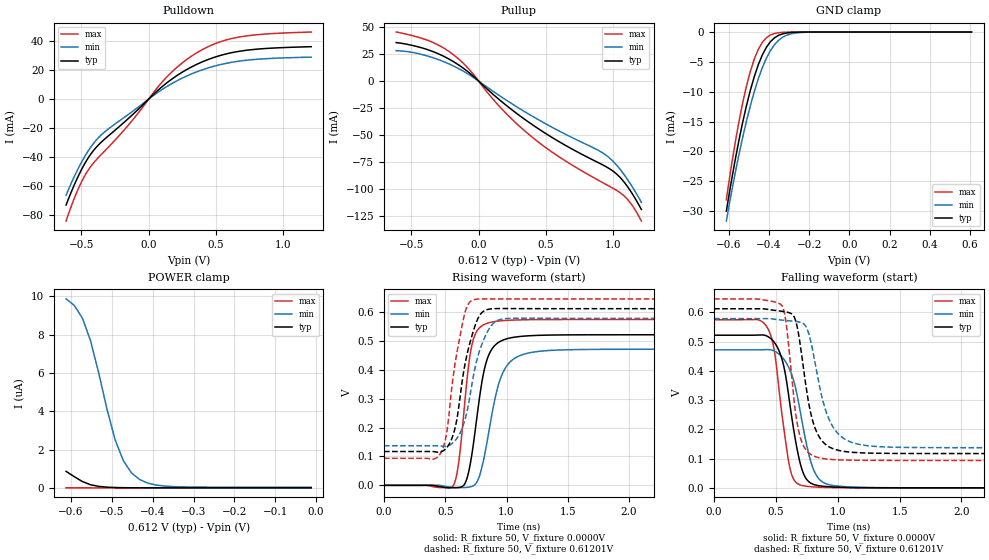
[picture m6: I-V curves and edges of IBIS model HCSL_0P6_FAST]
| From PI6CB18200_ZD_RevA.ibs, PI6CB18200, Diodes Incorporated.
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|   Model HCSL_OUT
[Model]   HCSL_0P6_FAST
Model_type Output
Vref=0.6000V
Vmeas=900mV
| variable   typ   min   max
C_comp   2.200pF   2.170pF   2.230pF
[Voltage Range]   0.61201V   0.57834V   0.64563V
[POWER Clamp Reference]   0.61201V   0.57834V   0.64563V
[GND Clamp Reference]   0.0000V   0.0000V   0.0000V
[Pullup Reference]   0.61201V   0.57834V   0.64563V
[Pulldown Reference]   0.0000V   0.0000V   0.0000V
[Temperature Range]   25   85   -40
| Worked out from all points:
|   slope of the pulldown table from 0 to 0.092 V, typ, clamps not added: 11.6 ohm
|   slope of the pullup table from 0 to 0.092 V, typ, clamps not added: 8.68 ohm
|   GND clamp passes 1 mA (typ) near -0.37 V on its own axis
|   falling waveform, R_fixture 50, V_fixture 0.0000V: 20-80 % time 122ps typ, 144ps min, 103ps max; typ from 0.522 V to 0 V
|   rising waveform, R_fixture 50, V_fixture 0.0000V: 20-80 % time 112ps typ, 141ps min, 85.6ps max; typ from 0 V to 0.522 V
|   falling waveform, R_fixture 50, V_fixture 0.61201V: 20-80 % time 119ps typ, 152ps min, 88.4ps max; typ from 0.612 V to 0.117 V
|   rising waveform, R_fixture 50, V_fixture 0.61201V: 20-80 % time 125ps typ, 140ps min, 109ps max; typ from 0.117 V to 0.612 V
[GND Clamp]
| Voltage   I(typ)   I(min)   I(max)
-612mV    -29.99mA   -31.66mA   -28.08mA
-572mV    -22.16mA   -24.32mA   -19.34mA
-552mV    -18.61mA   -20.97mA   -15.51mA
-512mV    -12.36mA   -14.94mA   -9.079mA
-492mV    -9.695mA   -12.28mA   -6.523mA
-472mV    -7.369mA   -9.876mA   -4.438mA
-432mV    -3.778mA   -5.894mA   -1.684mA
-392mV    -1.594mA   -3.08mA    -484.1uA
-352mV    -549.9uA   -1.379mA   -111.4uA
-312mV    -162.8uA   -534.4uA   -21.35uA
-232mV    -10.62uA   -61.45uA   -510.1nA
608mV     1.088nA    32.69nA    5.916pA
[POWER Clamp]
| Voltage   I(typ)   I(min)   I(max)
-612mV    861.3nA    9.861uA    1.622nA
-592mV    584.5nA    9.521uA    621.3pA
-572mV    326.4nA    8.851uA    247.2pA
-552mV    161.4nA    7.67uA     107.3pA
-512mV    36.25nA    4.113uA    34.36pA
-492mV    17.5nA     2.509uA    26.17pA
-472mV    8.826nA    1.421uA    22.46pA
-452mV    4.814nA    782.8nA    20.43pA
-432mV    2.956nA    433.1nA    19.01pA
-392mV    1.685nA    147.7nA    16.71pA
-352mV    1.395nA    67.95nA    14.59pA
-12.01mV  1.099nA    32.4nA     3.302pA
[Pulldown]
| Voltage   I(typ)   I(min)   I(max)
-612mV    -73mA      -66.14mA   -84.03mA
-552mV    -59.28mA   -53.51mA   -68.59mA
-492mV    -47.56mA   -42.53mA   -56.03mA
-432mV    -38.31mA   -33.48mA   -46.79mA
-352mV    -29.74mA   -24.73mA   -38.28mA
-152mV    -13.51mA   -10.63mA   -18.12mA
108mV     9.202mA    7.13mA     12.55mA
268mV     19.62mA    15.34mA    26.34mA
448mV     27.58mA    21.73mA    36.48mA
628mV     32.31mA    25.63mA    42.08mA
848mV     34.85mA    27.83mA    44.83mA
1.208V    36.24mA    29.04mA    46.35mA
[Pullup]
| Voltage   I(typ)   I(min)   I(max)
-612mV    35.7mA     28.22mA    45.49mA
-372mV    28.86mA    22.96mA    37.53mA
-212mV    19.86mA    15.46mA    26.73mA
-92.01mV  9.918mA    7.582mA    13.74mA
148mV     -16.65mA   -12.92mA   -22.6mA
348mV     -36mA      -28.82mA   -46.81mA
588mV     -55.49mA   -45.66mA   -69.46mA
908mV     -76.87mA   -65.61mA   -93.25mA
988mV     -82.6mA    -73.17mA   -98.72mA
1.088V    -94.91mA   -88.14mA   -107.4mA
1.148V    -105.9mA   -99.52mA   -116.7mA
1.208V    -119mA     -112.4mA   -129.7mA
[Falling Waveform]
R_fixture = 50
V_fixture = 0.0000V
V_fixture_min = 0.0000V
V_fixture_max = 0.0000V
|   Time   V(typ)   V(min)   V(max)
0s        521.6mV    471.5mV    574.5mV
350ps     522.1mV    471.5mV    575mV
440ps     515.7mV    472.4mV    540.2mV
490ps     495.4mV    466.8mV    461.3mV
540ps     451.9mV    451.2mV    280.2mV
610ps     294.6mV    405.5mV    73.25mV
710ps     63.43mV    229.7mV    8.233mV
820ps     9.766mV    48.12mV    2.841mV
980ps     2.602mV    6.949mV    765.6uV
5ns       10.03uV    12.5uV     7.762uV
[Rising Waveform]
R_fixture = 50
V_fixture = 0.0000V
V_fixture_min = 0.0000V
V_fixture_max = 0.0000V
|   Time   V(typ)   V(min)   V(max)
0s        4.666uV    5.74uV     3.844uV
570ps     -8.259mV   -7.435mV   2.236mV
610ps     -7.55mV    -7.857mV   80.2mV
660ps     5.497mV    -7.612mV   289.8mV
720ps     114.7mV    -3.356mV   490.9mV
800ps     360.2mV    63.96mV    553mV
860ps     456.2mV    196.1mV    563.7mV
980ps     504.6mV    398.6mV    570.8mV
1.22ns    518.9mV    461.6mV    573.9mV
5ns       521.6mV    471.5mV    574.5mV
[Falling Waveform]
R_fixture = 50
V_fixture = 0.61201V
V_fixture_min = 0.57834V
V_fixture_max = 0.64563V
|   Time   V(typ)   V(min)   V(max)
0s        612mV      578.3mV    645.6mV
550ps     603.2mV    573.3mV    622.3mV
590ps     600.5mV    571.5mV    537.5mV
640ps     589.8mV    569.5mV    323.2mV
690ps     507.5mV    566.6mV    183.3mV
760ps     301.4mV    534mV      121.5mV
840ps     181.5mV    373.9mV    103.8mV
970ps     132.5mV    202.4mV    96.43mV
1.22ns    119.1mV    145.1mV    93.96mV
5ns       117.2mV    137.2mV    93.58mV
[Rising Waveform]
R_fixture = 50
V_fixture = 0.61201V
V_fixture_min = 0.57834V
V_fixture_max = 0.64563V
|   Time   V(typ)   V(min)   V(max)
0s        117.2mV    137.2mV    93.58mV
460ps     115.5mV    136.7mV    109.6mV
510ps     129.4mV    135.7mV    176.6mV
560ps     169mV      146.2mV    361.3mV
630ps     335.5mV    189.5mV    537.7mV
680ps     457.3mV    260mV      621.7mV
740ps     548.8mV    401mV      643.9mV
860ps     610.4mV    543.6mV    645.9mV
990ps     612.4mV    577.5mV    645.7mV
5ns       612mV      578.3mV    645.6mV
[Ramp]
| variable   typ   min   max
dV/dt_r   0.31297V/112.21p   0.28288V/141.14p   0.34469V/85.594p
dV/dt_f   0.29690V/118.83p   0.26470V/151.73p   0.33122V/88.476p
R_load = 50
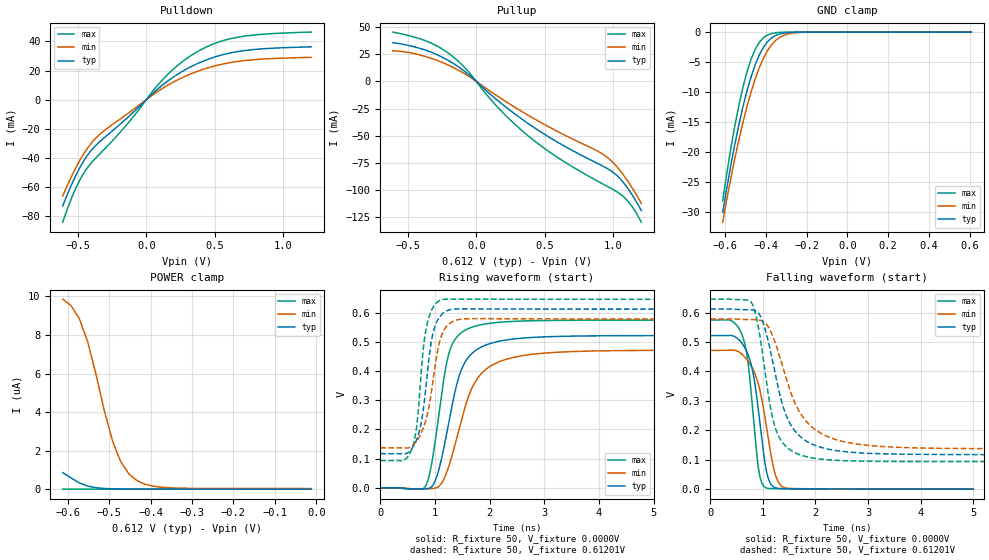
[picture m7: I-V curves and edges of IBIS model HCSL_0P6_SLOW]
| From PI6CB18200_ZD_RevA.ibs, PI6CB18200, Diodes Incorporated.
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[Model]   HCSL_0P6_SLOW
Model_type Output
Vref=0.6000V
Vmeas=900mV
| variable   typ   min   max
C_comp   2.200pF   2.170pF   2.230pF
[Voltage Range]   0.61201V   0.57834V   0.64563V
[POWER Clamp Reference]   0.61201V   0.57834V   0.64563V
[GND Clamp Reference]   0.0000V   0.0000V   0.0000V
[Pullup Reference]   0.61201V   0.57834V   0.64563V
[Pulldown Reference]   0.0000V   0.0000V   0.0000V
[Temperature Range]   25   85   -40
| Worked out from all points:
|   slope of the pulldown table from 0 to 0.092 V, typ, clamps not added: 11.6 ohm
|   slope of the pullup table from 0 to 0.092 V, typ, clamps not added: 8.68 ohm
|   GND clamp passes 1 mA (typ) near -0.37 V on its own axis
|   falling waveform, R_fixture 50, V_fixture 0.0000V: 20-80 % time 242ps typ, 298ps min, 191ps max; typ from 0.522 V to 0 V
|   rising waveform, R_fixture 50, V_fixture 0.0000V: 20-80 % time 387ps typ, 499ps min, 286ps max; typ from 0 V to 0.522 V
|   falling waveform, R_fixture 50, V_fixture 0.61201V: 20-80 % time 449ps typ, 602ps min, 315ps max; typ from 0.612 V to 0.117 V
|   rising waveform, R_fixture 50, V_fixture 0.61201V: 20-80 % time 203ps typ, 248ps min, 168ps max; typ from 0.117 V to 0.612 V
[GND Clamp]
| Voltage   I(typ)   I(min)   I(max)
-612mV    -29.99mA   -31.66mA   -28.08mA
-572mV    -22.16mA   -24.32mA   -19.34mA
-552mV    -18.61mA   -20.97mA   -15.51mA
-512mV    -12.36mA   -14.94mA   -9.079mA
-492mV    -9.695mA   -12.28mA   -6.523mA
-472mV    -7.369mA   -9.876mA   -4.438mA
-432mV    -3.778mA   -5.894mA   -1.684mA
-392mV    -1.594mA   -3.08mA    -484.1uA
-352mV    -549.9uA   -1.379mA   -111.4uA
-312mV    -162.8uA   -534.4uA   -21.35uA
-232mV    -10.62uA   -61.45uA   -510.1nA
608mV     1.088nA    32.69nA    5.916pA
[POWER Clamp]
| Voltage   I(typ)   I(min)   I(max)
-612mV    861.3nA    9.861uA    1.622nA
-592mV    584.5nA    9.521uA    621.3pA
-572mV    326.4nA    8.851uA    247.2pA
-552mV    161.4nA    7.67uA     107.3pA
-512mV    36.25nA    4.113uA    34.36pA
-492mV    17.5nA     2.509uA    26.17pA
-472mV    8.826nA    1.421uA    22.46pA
-452mV    4.814nA    782.8nA    20.43pA
-432mV    2.956nA    433.1nA    19.01pA
-392mV    1.685nA    147.7nA    16.71pA
-352mV    1.395nA    67.95nA    14.59pA
-12.01mV  1.099nA    32.4nA     3.302pA
[Pulldown]
| Voltage   I(typ)   I(min)   I(max)
-612mV    -73mA      -66.14mA   -84.03mA
-552mV    -59.28mA   -53.51mA   -68.59mA
-492mV    -47.56mA   -42.53mA   -56.03mA
-432mV    -38.31mA   -33.48mA   -46.79mA
-352mV    -29.74mA   -24.73mA   -38.28mA
-152mV    -13.51mA   -10.63mA   -18.12mA
108mV     9.202mA    7.13mA     12.55mA
268mV     19.62mA    15.34mA    26.34mA
448mV     27.58mA    21.73mA    36.48mA
628mV     32.31mA    25.63mA    42.08mA
848mV     34.85mA    27.83mA    44.83mA
1.208V    36.24mA    29.04mA    46.35mA
[Pullup]
| Voltage   I(typ)   I(min)   I(max)
-612mV    35.7mA     28.22mA    45.49mA
-372mV    28.86mA    22.96mA    37.53mA
-212mV    19.86mA    15.46mA    26.73mA
-92.01mV  9.918mA    7.582mA    13.74mA
148mV     -16.65mA   -12.92mA   -22.6mA
348mV     -36mA      -28.82mA   -46.81mA
588mV     -55.49mA   -45.66mA   -69.46mA
908mV     -76.87mA   -65.61mA   -93.25mA
988mV     -82.6mA    -73.17mA   -98.72mA
1.088V    -94.91mA   -88.14mA   -107.4mA
1.148V    -105.9mA   -99.52mA   -116.7mA
1.208V    -119mA     -112.4mA   -129.7mA
[Falling Waveform]
R_fixture = 50
V_fixture = 0.0000V
V_fixture_min = 0.0000V
V_fixture_max = 0.0000V
|   Time   V(typ)   V(min)   V(max)
0s        521.6mV    471.5mV    574.5mV
400ps     522mV      471.9mV    572.1mV
620ps     491.4mV    455.6mV    516.7mV
720ps     456.3mV    435.4mV    427.2mV
820ps     388.6mV    404.1mV    240.3mV
930ps     245.5mV    346.3mV    55.54mV
1.04ns    89.64mV    244.4mV    6.396mV
1.23ns    5.038mV    53.9mV     1.793mV
1.41ns    1.808mV    5.117mV    1.401mV
5ns       18.06uV    35.2uV     9.849uV
[Rising Waveform]
R_fixture = 50
V_fixture = 0.0000V
V_fixture_min = 0.0000V
V_fixture_max = 0.0000V
|   Time   V(typ)   V(min)   V(max)
0s        4.784uV    5.905uV    3.914uV
820ps     -3.36mV    -2.914mV   4.181mV
920ps     732.2uV    -2.643mV   63.21mV
1.02ns    32.1mV     208.6uV    180.1mV
1.26ns    231.1mV    77.9mV     463.3mV
1.46ns    393.4mV    214.8mV    528.1mV
1.72ns    467.4mV    357.9mV    552.9mV
2.14ns    500.8mV    429.2mV    566.4mV
3ns       517.2mV    461.5mV    573.1mV
10ns      521.6mV    471.5mV    574.5mV
[Falling Waveform]
R_fixture = 50
V_fixture = 0.61201V
V_fixture_min = 0.57834V
V_fixture_max = 0.64563V
|   Time   V(typ)   V(min)   V(max)
0s        612mV      578.3mV    645.6mV
800ps     608.6mV    576.1mV    628.4mV
1ns       567.4mV    570.3mV    453mV
1.14ns    473.2mV    539.2mV    282mV
1.24ns    388.1mV    494.4mV    206.1mV
1.44ns    251.9mV    378.2mV    145.1mV
1.72ns    177.1mV    255.5mV    115.7mV
2.22ns    136.7mV    179.4mV    100.2mV
3.2ns     120.5mV    145.6mV    94.42mV
10ns      117.2mV    137.2mV    93.58mV
[Rising Waveform]
R_fixture = 50
V_fixture = 0.61201V
V_fixture_min = 0.57834V
V_fixture_max = 0.64563V
|   Time   V(typ)   V(min)   V(max)
0s        117.2mV    137.2mV    93.58mV
420ps     116.5mV    137.1mV    93.3mV
580ps     135.3mV    143.6mV    134.3mV
670ps     168mV      162mV      217.2mV
780ps     257.5mV    202mV      465.2mV
840ps     354.9mV    236.8mV    546.6mV
950ps     517.4mV    348.9mV    613.1mV
1.1ns     589mV      510.9mV    642.7mV
1.55ns    613mV      578.9mV    646.2mV
7ns       612mV      578.3mV    645.6mV
[Ramp]
| variable   typ   min   max
dV/dt_r   0.31297V/388.46p   0.28288V/498.66p   0.34469V/285.96p
dV/dt_f   0.29690V/449.40p   0.26470V/602.51p   0.33122V/315.07p
R_load = 50
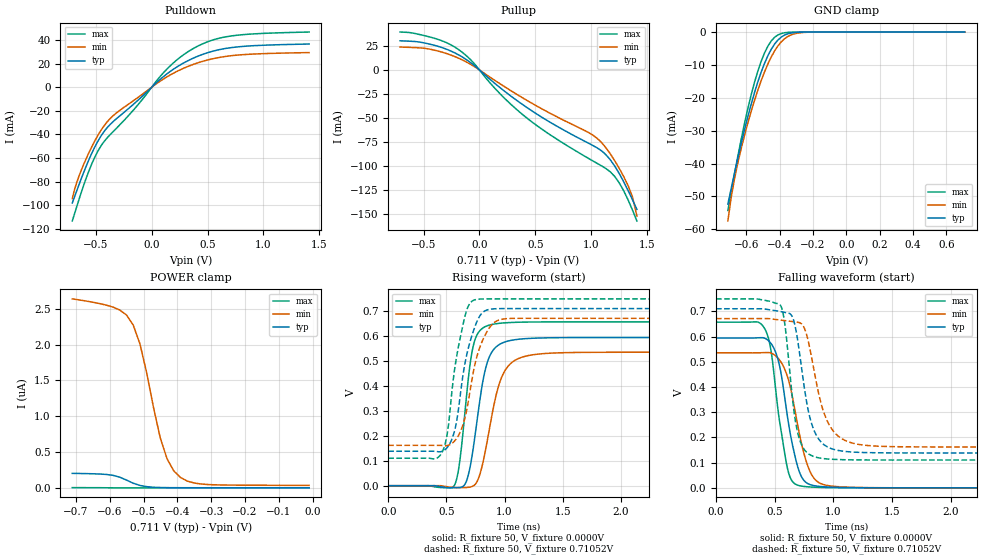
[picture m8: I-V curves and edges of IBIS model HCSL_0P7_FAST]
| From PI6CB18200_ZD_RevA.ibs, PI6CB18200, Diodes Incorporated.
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[Model]   HCSL_0P7_FAST
Model_type Output
Vref=0.7000V
Vmeas=900mV
| variable   typ   min   max
C_comp   2.200pF   2.170pF   2.230pF
[Voltage Range]   0.71052V   0.67147V   0.74949V
[POWER Clamp Reference]   0.71052V   0.67147V   0.74949V
[GND Clamp Reference]   0.0000V   0.0000V   0.0000V
[Pullup Reference]   0.71052V   0.67147V   0.74949V
[Pulldown Reference]   0.0000V   0.0000V   0.0000V
[Temperature Range]   25   85   -40
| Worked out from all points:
|   slope of the pulldown table from 0 to 0.107 V, typ, clamps not added: 11.7 ohm
|   slope of the pullup table from 0 to 0.107 V, typ, clamps not added: 9.74 ohm
|   GND clamp passes 1 mA (typ) near -0.37 V on its own axis
|   falling waveform, R_fixture 50, V_fixture 0.0000V: 20-80 % time 131ps typ, 151ps min, 113ps max; typ from 0.594 V to 0 V
|   rising waveform, R_fixture 50, V_fixture 0.0000V: 20-80 % time 119ps typ, 149ps min, 92.5ps max; typ from 0 V to 0.594 V
|   falling waveform, R_fixture 50, V_fixture 0.71052V: 20-80 % time 124ps typ, 157ps min, 93.3ps max; typ from 0.711 V to 0.138 V
|   rising waveform, R_fixture 50, V_fixture 0.71052V: 20-80 % time 130ps typ, 144ps min, 115ps max; typ from 0.138 V to 0.711 V
[GND Clamp]
| Voltage   I(typ)   I(min)   I(max)
-710.5mV  -52.32mA   -57.46mA   -54.26mA
-690.5mV  -47.56mA   -50.29mA   -48.61mA
-650.5mV  -38.34mA   -39.76mA   -37.72mA
-590.5mV  -25.69mA   -27.63mA   -23.23mA
-550.5mV  -18.37mA   -20.75mA   -15.25mA
-490.5mV  -9.518mA   -12.1mA    -6.355mA
-470.5mV  -7.215mA   -9.716mA   -4.304mA
-430.5mV  -3.675mA   -5.774mA   -1.616mA
-390.5mV  -1.539mA   -3mA       -460.2uA
-350.5mV  -527.1uA   -1.335mA   -105.2uA
-270.5mV  -41.31uA   -180uA     -3.245uA
709.5mV   1.155nA    34.32nA    1.818pA
[POWER Clamp]
| Voltage   I(typ)   I(min)   I(max)
-710.5mV  202.2nA    2.638uA    2.798nA
-570.5mV  149.4nA    2.483uA    234pA
-550.5mV  108.8nA    2.414uA    105.5pA
-530.5mV  64.81nA    2.274uA    56.58pA
-510.5mV  33.41nA    2.009uA    37.7pA
-490.5mV  16.56nA    1.602uA    30pA
-450.5mV  4.682nA    697.5nA    24.52pA
-430.5mV  2.929nA    406.4nA    23.13pA
-410.5mV  2.112nA    236.4nA    21.95pA
-390.5mV  1.728nA    143.7nA    20.85pA
-310.5mV  1.373nA    46.52nA    16.62pA
-10.52mV  1.163nA    33.88nA    838.6fA
[Pulldown]
| Voltage   I(typ)   I(min)   I(max)
-710.5mV  -98.12mA   -94.39mA   -113.4mA
-650.5mV  -82.61mA   -75.33mA   -95.15mA
-530.5mV  -54.84mA   -49.39mA   -63.74mA
-470.5mV  -43.95mA   -39.05mA   -52.33mA
-390.5mV  -33.42mA   -28.49mA   -42.08mA
-150.5mV  -13.38mA   -10.53mA   -17.95mA
109.5mV   9.316mA    7.219mA    12.7mA
249.5mV   18.59mA    14.52mA    24.99mA
449.5mV   27.63mA    21.78mA    36.54mA
649.5mV   32.68mA    25.95mA    42.5mA
909.5mV   35.21mA    28.14mA    45.22mA
1.409V    36.65mA    29.38mA    46.82mA
[Pullup]
| Voltage   I(typ)   I(min)   I(max)
-710.5mV  30.31mA    23.83mA    39.46mA
-390.5mV  25.24mA    20.24mA    32.51mA
-190.5mV  15.92mA    12.39mA    21.49mA
-70.52mV  6.87mA     5.237mA    9.578mA
169.5mV   -17.03mA   -13.28mA   -23mA
389.5mV   -36.3mA    -29.26mA   -46.74mA
649.5mV   -55.62mA   -46.15mA   -68.79mA
1.029V    -79.58mA   -69.05mA   -95.65mA
1.169V    -93.26mA   -87.06mA   -105.9mA
1.289V    -116mA     -110.6mA   -125.4mA
1.369V    -135.1mA   -132mA     -145.7mA
1.409V    -145.1mA   -152.1mA   -157.3mA
[Falling Waveform]
R_fixture = 50
V_fixture = 0.0000V
V_fixture_min = 0.0000V
V_fixture_max = 0.0000V
|   Time   V(typ)   V(min)   V(max)
0s        594.4mV    535.5mV    657.3mV
350ps     595.1mV    535.6mV    658.2mV
420ps     592.6mV    536.7mV    627.2mV
470ps     571.8mV    534.4mV    540.8mV
530ps     506.3mV    513.6mV    302.8mV
610ps     279.3mV    439.6mV    74.7mV
700ps     77.69mV    239.1mV    9.97mV
810ps     11.58mV    56.54mV    3.221mV
980ps     2.696mV    7.269mV    816.9uV
5ns       11.41uV    14.18uV    8.872uV
[Rising Waveform]
R_fixture = 50
V_fixture = 0.0000V
V_fixture_min = 0.0000V
V_fixture_max = 0.0000V
|   Time   V(typ)   V(min)   V(max)
0s        5.307uV    6.449uV    4.595uV
570ps     -8.244mV   -7.434mV   2.191mV
610ps     -7.477mV   -7.853mV   81.04mV
670ps     15.19mV    -7.322mV   345mV
730ps     147.3mV    -1.181mV   558.5mV
810ps     409.2mV    84.22mV    631.3mV
870ps     517.2mV    227.6mV    644.3mV
1ns       576.1mV    458.8mV    653.2mV
1.24ns    591.5mV    524.9mV    656.6mV
5ns       594.4mV    535.5mV    657.3mV
[Falling Waveform]
R_fixture = 50
V_fixture = 0.71052V
V_fixture_min = 0.67147V
V_fixture_max = 0.74949V
|   Time   V(typ)   V(min)   V(max)
0s        710.5mV    671.5mV    749.5mV
550ps     699.5mV    665.8mV    723.6mV
590ps     695.5mV    663.5mV    637.2mV
650ps     679mV      659.8mV    360.7mV
690ps     602.8mV    657.3mV    231.2mV
760ps     374.2mV    625.2mV    147.3mV
850ps     213mV      429.1mV    121.7mV
990ps     154.5mV    231.2mV    113.3mV
1.24ns    140.3mV    170.6mV    110.7mV
5ns       138.2mV    161.9mV    110.3mV
[Rising Waveform]
R_fixture = 50
V_fixture = 0.71052V
V_fixture_min = 0.67147V
V_fixture_max = 0.74949V
|   Time   V(typ)   V(min)   V(max)
0s        138.2mV    161.9mV    110.3mV
460ps     137.3mV    161.4mV    131.6mV
510ps     154.7mV    161.1mV    215mV
560ps     203.2mV    174.4mV    429.1mV
630ps     401.4mV    227.7mV    617.7mV
690ps     554.2mV    341.9mV    722mV
750ps     643.5mV    495.8mV    746.2mV
870ps     707.3mV    633.4mV    749.4mV
1.02ns    710.5mV    670.1mV    749.4mV
5ns       710.5mV    671.5mV    749.5mV
[Ramp]
| variable   typ   min   max
dV/dt_r   0.35665V/119.45p   0.32129V/148.62p   0.39436V/92.531p
dV/dt_f   0.34337V/123.98p   0.30571V/157.20p   0.38352V/93.305p
R_load = 50
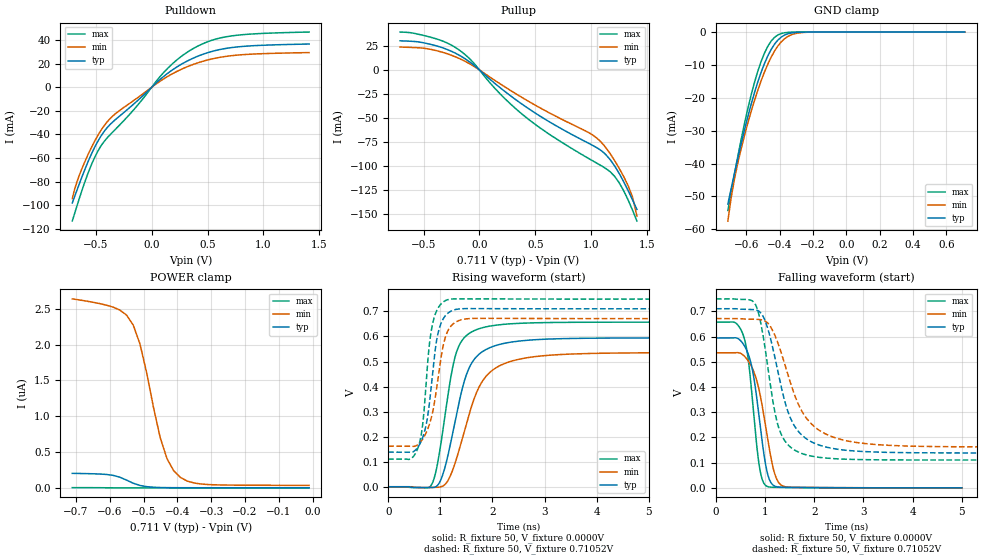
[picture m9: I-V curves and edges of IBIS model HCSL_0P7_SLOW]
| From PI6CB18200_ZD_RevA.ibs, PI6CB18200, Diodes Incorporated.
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[Model]   HCSL_0P7_SLOW
Model_type Output
Vref=0.7000V
Vmeas=900mV
| variable   typ   min   max
C_comp   2.200pF   2.170pF   2.230pF
[Voltage Range]   0.71052V   0.67147V   0.74949V
[POWER Clamp Reference]   0.71052V   0.67147V   0.74949V
[GND Clamp Reference]   0.0000V   0.0000V   0.0000V
[Pullup Reference]   0.71052V   0.67147V   0.74949V
[Pulldown Reference]   0.0000V   0.0000V   0.0000V
[Temperature Range]   25   85   -40
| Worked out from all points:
|   slope of the pulldown table from 0 to 0.107 V, typ, clamps not added: 11.7 ohm
|   slope of the pullup table from 0 to 0.107 V, typ, clamps not added: 9.74 ohm
|   GND clamp passes 1 mA (typ) near -0.37 V on its own axis
|   falling waveform, R_fixture 50, V_fixture 0.0000V: 20-80 % time 252ps typ, 306ps min, 205ps max; typ from 0.594 V to 0 V
|   rising waveform, R_fixture 50, V_fixture 0.0000V: 20-80 % time 416ps typ, 527ps min, 313ps max; typ from 0 V to 0.594 V
|   falling waveform, R_fixture 50, V_fixture 0.71052V: 20-80 % time 471ps typ, 624ps min, 335ps max; typ from 0.711 V to 0.138 V
|   rising waveform, R_fixture 50, V_fixture 0.71052V: 20-80 % time 206ps typ, 250ps min, 170ps max; typ from 0.138 V to 0.711 V
[GND Clamp]
| Voltage   I(typ)   I(min)   I(max)
-710.5mV  -52.32mA   -57.46mA   -54.26mA
-690.5mV  -47.56mA   -50.29mA   -48.61mA
-650.5mV  -38.34mA   -39.76mA   -37.72mA
-590.5mV  -25.69mA   -27.63mA   -23.23mA
-550.5mV  -18.37mA   -20.75mA   -15.25mA
-490.5mV  -9.518mA   -12.1mA    -6.355mA
-470.5mV  -7.215mA   -9.716mA   -4.304mA
-430.5mV  -3.675mA   -5.774mA   -1.616mA
-390.5mV  -1.539mA   -3mA       -460.2uA
-350.5mV  -527.1uA   -1.335mA   -105.2uA
-270.5mV  -41.31uA   -180uA     -3.245uA
709.5mV   1.155nA    34.32nA    1.818pA
[POWER Clamp]
| Voltage   I(typ)   I(min)   I(max)
-710.5mV  202.2nA    2.638uA    2.798nA
-570.5mV  149.4nA    2.483uA    234pA
-550.5mV  108.8nA    2.414uA    105.5pA
-530.5mV  64.81nA    2.274uA    56.58pA
-510.5mV  33.41nA    2.009uA    37.7pA
-490.5mV  16.56nA    1.602uA    30pA
-450.5mV  4.682nA    697.5nA    24.52pA
-430.5mV  2.929nA    406.4nA    23.13pA
-410.5mV  2.112nA    236.4nA    21.95pA
-390.5mV  1.728nA    143.7nA    20.85pA
-310.5mV  1.373nA    46.52nA    16.62pA
-10.52mV  1.163nA    33.88nA    838.6fA
[Pulldown]
| Voltage   I(typ)   I(min)   I(max)
-710.5mV  -98.12mA   -94.39mA   -113.4mA
-650.5mV  -82.61mA   -75.33mA   -95.15mA
-530.5mV  -54.84mA   -49.39mA   -63.74mA
-470.5mV  -43.95mA   -39.05mA   -52.33mA
-390.5mV  -33.42mA   -28.49mA   -42.08mA
-150.5mV  -13.38mA   -10.53mA   -17.95mA
109.5mV   9.316mA    7.219mA    12.7mA
249.5mV   18.59mA    14.52mA    24.99mA
449.5mV   27.63mA    21.78mA    36.54mA
649.5mV   32.68mA    25.95mA    42.5mA
909.5mV   35.21mA    28.14mA    45.22mA
1.409V    36.65mA    29.38mA    46.82mA
[Pullup]
| Voltage   I(typ)   I(min)   I(max)
-710.5mV  30.31mA    23.83mA    39.46mA
-390.5mV  25.24mA    20.24mA    32.51mA
-190.5mV  15.92mA    12.39mA    21.49mA
-70.52mV  6.87mA     5.237mA    9.578mA
169.5mV   -17.03mA   -13.28mA   -23mA
389.5mV   -36.3mA    -29.26mA   -46.74mA
649.5mV   -55.62mA   -46.15mA   -68.79mA
1.029V    -79.58mA   -69.05mA   -95.65mA
1.169V    -93.26mA   -87.06mA   -105.9mA
1.289V    -116mA     -110.6mA   -125.4mA
1.369V    -135.1mA   -132mA     -145.7mA
1.409V    -145.1mA   -152.1mA   -157.3mA
[Falling Waveform]
R_fixture = 50
V_fixture = 0.0000V
V_fixture_min = 0.0000V
V_fixture_max = 0.0000V
|   Time   V(typ)   V(min)   V(max)
0s        594.4mV    535.5mV    657.3mV
390ps     595.2mV    535.9mV    655.2mV
570ps     566mV      523.6mV    595.9mV
650ps     533.6mV    505mV      517.8mV
730ps     478.8mV    477.8mV    371.2mV
870ps     292.5mV    394.2mV    100.8mV
1.02ns    80.71mV    230.5mV    7.919mV
1.19ns    7.292mV    58.81mV    2.179mV
1.38ns    2.169mV    5.766mV    1.532mV
5ns       19.5uV     37.07uV    10.95uV
[Rising Waveform]
R_fixture = 50
V_fixture = 0.0000V
V_fixture_min = 0.0000V
V_fixture_max = 0.0000V
|   Time   V(typ)   V(min)   V(max)
0s        5.398uV    6.616uV    4.481uV
840ps     -3.235mV   -2.883mV   11.44mV
1.04ns    44.16mV    1.97mV     212.7mV
1.2ns     176.6mV    47.45mV    435.9mV
1.3ns     278mV      105.1mV    531mV
1.52ns    458.6mV    265.7mV    607.1mV
1.76ns    532.2mV    404.8mV    632.1mV
2.18ns    570.6mV    487.4mV    647.9mV
3.1ns     589.9mV    525.3mV    655.8mV
10ns      594.4mV    535.5mV    657.3mV
[Falling Waveform]
R_fixture = 50
V_fixture = 0.71052V
V_fixture_min = 0.67147V
V_fixture_max = 0.74949V
|   Time   V(typ)   V(min)   V(max)
0s        710.5mV    671.5mV    749.5mV
800ps     706mV      668.8mV    727.9mV
1.02ns    651.7mV    658.9mV    525.6mV
1.18ns    533.5mV    612.9mV    318mV
1.28ns    442.6mV    562.9mV    235.9mV
1.5ns     282.9mV    425.7mV    164.1mV
1.78ns    203.4mV    293.1mV    134mV
2.28ns    159.8mV    209.1mV    117.4mV
3.2ns     142.4mV    172.5mV    111.3mV
10ns      138.2mV    161.9mV    110.3mV
[Rising Waveform]
R_fixture = 50
V_fixture = 0.71052V
V_fixture_min = 0.67147V
V_fixture_max = 0.74949V
|   Time   V(typ)   V(min)   V(max)
0s        138.2mV    161.9mV    110.3mV
420ps     137.6mV    161.9mV    110.5mV
570ps     158.1mV    168.8mV    154.6mV
660ps     195.7mV    190.1mV    246.5mV
730ps     249.4mV    216.4mV    421mV
840ps     430.8mV    286.7mV    638.8mV
950ps     607.7mV    424.7mV    711.4mV
1.11ns    686.4mV    605.4mV    744.6mV
1.55ns    711.4mV    671.4mV    750.1mV
7ns       710.5mV    671.5mV    749.5mV
[Ramp]
| variable   typ   min   max
dV/dt_r   0.35665V/417.59p   0.32130V/527.39p   0.39436V/313.27p
dV/dt_f   0.34337V/471.33p   0.30571V/624.34p   0.38352V/334.74p
R_load = 50
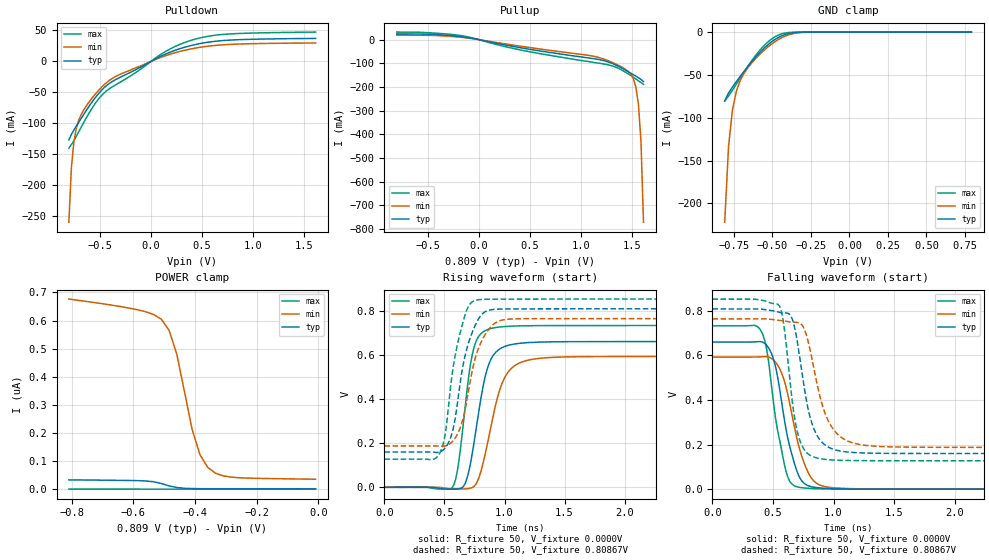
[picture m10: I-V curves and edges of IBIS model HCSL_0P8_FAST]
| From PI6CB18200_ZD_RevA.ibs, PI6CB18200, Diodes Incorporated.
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[Model]   HCSL_0P8_FAST
Model_type Output
Vref=0.8000V
Vmeas=900mV
| variable   typ   min   max
C_comp   2.200pF   2.170pF   2.230pF
[Voltage Range]   0.80867V   0.76428V   0.85294V
[POWER Clamp Reference]   0.80867V   0.76428V   0.85294V
[GND Clamp Reference]   0.0000V   0.0000V   0.0000V
[Pullup Reference]   0.80867V   0.76428V   0.85294V
[Pulldown Reference]   0.0000V   0.0000V   0.0000V
[Temperature Range]   25   85   -40
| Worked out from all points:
|   slope of the pulldown table from 0 to 0.121 V, typ, clamps not added: 11.9 ohm
|   slope of the pullup table from 0 to 0.121 V, typ, clamps not added: 11.2 ohm
|   GND clamp passes 1 mA (typ) near -0.37 V on its own axis
|   falling waveform, R_fixture 50, V_fixture 0.0000V: 20-80 % time 139ps typ, 157ps min, 121ps max; typ from 0.66 V to 0 V
|   rising waveform, R_fixture 50, V_fixture 0.0000V: 20-80 % time 127ps typ, 157ps min, 99.6ps max; typ from 0 V to 0.66 V
|   falling waveform, R_fixture 50, V_fixture 0.80867V: 20-80 % time 130ps typ, 164ps min, 98.3ps max; typ from 0.809 V to 0.16 V
|   rising waveform, R_fixture 50, V_fixture 0.80867V: 20-80 % time 134ps typ, 147ps min, 120ps max; typ from 0.16 V to 0.809 V
[GND Clamp]
| Voltage   I(typ)   I(min)   I(max)
-808.7mV  -80.37mA   -222mA     -80.74mA
-783.7mV  -71.17mA   -133.6mA   -74.56mA
-758.7mV  -64.24mA   -91.22mA   -67.91mA
-733.7mV  -57.98mA   -69.4mA    -60.91mA
-708.7mV  -51.92mA   -56.75mA   -53.79mA
-658.7mV  -40.22mA   -41.7mA    -39.91mA
-583.7mV  -24.39mA   -26.41mA   -21.78mA
-508.7mV  -11.91mA   -14.51mA   -8.63mA
-458.7mV  -6.021mA   -8.437mA   -3.317mA
-408.7mV  -2.346mA   -4.117mA   -840.2uA
-308.7mV  -146.6uA   -492.3uA   -18.47uA
791.3mV   1.208nA    35.61nA    1.245pA
[POWER Clamp]
| Voltage   I(typ)   I(min)   I(max)
-808.7mV  33.02nA    676.5nA    257.7pA
-583.7mV  30.32nA    637.8nA    188.8pA
-533.7mV  26.33nA    621.6nA    64.6pA
-508.7mV  20.08nA    604.6nA    40.81pA
-483.7mV  11.74nA    565.4nA    32.71pA
-458.7mV  5.847nA    479.8nA    29.41pA
-408.7mV  2.125nA    211.3nA    26.04pA
-383.7mV  1.712nA    122.8nA    24.67pA
-358.7mV  1.545nA    77.92nA    23.35pA
-333.7mV  1.471nA    57.06nA    22.03pA
-258.7mV  1.389nA    40.71nA    18.08pA
-8.67mV   1.225nA    35.32nA    4.944pA
[Pulldown]
| Voltage   I(typ)   I(min)   I(max)
-808.7mV  -126.9mA   -259.7mA   -140.3mA
-783.7mV  -117.8mA   -171.3mA   -134.3mA
-758.7mV  -110.7mA   -128.8mA   -127.7mA
-733.7mV  -104.2mA   -106.7mA   -120.4mA
-683.7mV  -91.18mA   -84.64mA   -105.2mA
-633.7mV  -78.39mA   -71.22mA   -90.23mA
-508.7mV  -50.6mA    -45.42mA   -59.21mA
-408.7mV  -35.42mA   -30.55mA   -44.02mA
141.3mV   11.67mA    9.059mA    15.86mA
441.3mV   27.35mA    21.54mA    36.19mA
791.3mV   34.41mA    27.45mA    44.37mA
1.616V    36.98mA    29.67mA    47.19mA
[Pullup]
| Voltage   I(typ)   I(min)   I(max)
-808.7mV  24.53mA    19.25mA    32.08mA
-183.7mV  13.04mA    10.2mA     17.5mA
391.3mV   -32.8mA    -26.53mA   -42.02mA
1.066V    -76.76mA   -65.87mA   -92.16mA
1.266V    -93.85mA   -88.49mA   -106.1mA
1.441V    -129.3mA   -125.9mA   -137.9mA
1.491V    -141.7mA   -145.7mA   -151.7mA
1.516V    -148mA     -164.6mA   -159mA
1.541V    -154.4mA   -200.1mA   -166.5mA
1.566V    -161mA     -272.7mA   -174.1mA
1.591V    -168.1mA   -428.9mA   -181.6mA
1.616V    -177.3mA   -772.1mA   -188.9mA
[Falling Waveform]
R_fixture = 50
V_fixture = 0.0000V
V_fixture_min = 0.0000V
V_fixture_max = 0.0000V
|   Time   V(typ)   V(min)   V(max)
0s        660.3mV    592.9mV    733.1mV
400ps     662mV      594mV      711.5mV
450ps     644.6mV    594.7mV    622.6mV
510ps     573.8mV    576.4mV    364.4mV
600ps     293.5mV    475mV      98mV
640ps     188.7mV    380.6mV    34.65mV
700ps     77.67mV    222.9mV    10.39mV
820ps     10.72mV    48.23mV    3.063mV
990ps     2.597mV    6.972mV    791.6uV
5ns       12.66uV    15.7uV     9.886uV
[Rising Waveform]
R_fixture = 50
V_fixture = 0.0000V
V_fixture_min = 0.0000V
V_fixture_max = 0.0000V
|   Time   V(typ)   V(min)   V(max)
0s        5.947uV    9.192uV    4.869uV
570ps     -8.228mV   -7.424mV   2.771mV
610ps     -7.413mV   -7.846mV   84.08mV
670ps     15.16mV    -7.299mV   354.9mV
740ps     181.5mV    1.892mV    621.9mV
830ps     480.4mV    128.8mV    707.3mV
900ps     592.6mV    311mV      721.4mV
1.03ns    643.2mV    522.2mV    729.4mV
1.3ns     658mV      584.8mV    732.6mV
6ns       660.3mV    592.9mV    733.1mV
[Falling Waveform]
R_fixture = 50
V_fixture = 0.80867V
V_fixture_min = 0.76428V
V_fixture_max = 0.85294V
|   Time   V(typ)   V(min)   V(max)
0s        808.7mV    764.3mV    852.9mV
550ps     794.2mV    757.7mV    824.9mV
590ps     791.1mV    754.7mV    735.9mV
650ps     775.4mV    749.8mV    439.7mV
700ps     665.8mV    748.5mV    260mV
770ps     417.1mV    701.9mV    169.1mV
860ps     245.3mV    482.6mV    140.6mV
1ns       178.5mV    267.5mV    130.8mV
1.26ns    162.3mV    197mV      127.9mV
5ns       160mV      187.5mV    127.5mV
[Rising Waveform]
R_fixture = 50
V_fixture = 0.80867V
V_fixture_min = 0.76428V
V_fixture_max = 0.85294V
|   Time   V(typ)   V(min)   V(max)
0s        160mV      187.5mV    127.5mV
460ps     159.9mV    186.9mV    154.2mV
510ps     181.2mV    187.4mV    254.6mV
560ps     239.8mV    203.8mV    496.7mV
620ps     430.6mV    254.6mV    676.4mV
680ps     614.9mV    375.3mV    795.2mV
760ps     738.5mV    592.7mV    847.4mV
890ps     804.4mV    729.2mV    852.4mV
1.04ns    808.2mV    762mV      852.6mV
5ns       808.7mV    764.3mV    852.9mV
[Ramp]
| variable   typ   min   max
dV/dt_r   0.39616V/127.35p   0.35575V/156.49p   0.43987V/99.592p
dV/dt_f   0.38922V/129.63p   0.34604V/163.48p   0.43528V/98.315p
R_load = 50
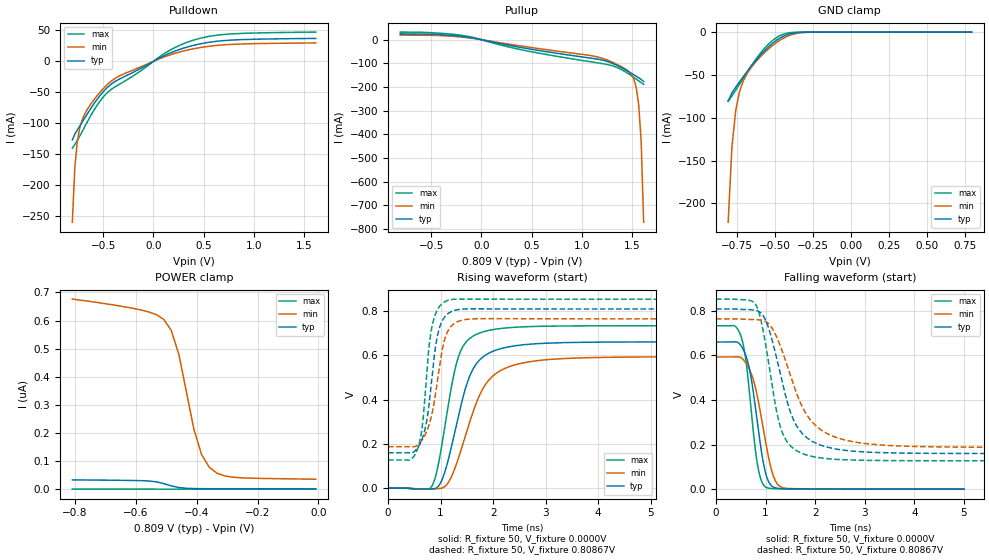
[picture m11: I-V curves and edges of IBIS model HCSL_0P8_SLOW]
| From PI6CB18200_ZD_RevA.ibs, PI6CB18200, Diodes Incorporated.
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[Model]   HCSL_0P8_SLOW
Model_type Output
Vref=0.8000V
Vmeas=900mV
| variable   typ   min   max
C_comp   2.200pF   2.170pF   2.230pF
[Voltage Range]   0.80867V   0.76428V   0.85294V
[POWER Clamp Reference]   0.80867V   0.76428V   0.85294V
[GND Clamp Reference]   0.0000V   0.0000V   0.0000V
[Pullup Reference]   0.80867V   0.76428V   0.85294V
[Pulldown Reference]   0.0000V   0.0000V   0.0000V
[Temperature Range]   25   85   -40
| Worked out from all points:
|   slope of the pulldown table from 0 to 0.121 V, typ, clamps not added: 11.9 ohm
|   slope of the pullup table from 0 to 0.121 V, typ, clamps not added: 11.2 ohm
|   GND clamp passes 1 mA (typ) near -0.37 V on its own axis
|   falling waveform, R_fixture 50, V_fixture 0.0000V: 20-80 % time 259ps typ, 310ps min, 213ps max; typ from 0.66 V to 0 V
|   rising waveform, R_fixture 50, V_fixture 0.0000V: 20-80 % time 447ps typ, 558ps min, 343ps max; typ from 0 V to 0.66 V
|   falling waveform, R_fixture 50, V_fixture 0.80867V: 20-80 % time 492ps typ, 647ps min, 355ps max; typ from 0.809 V to 0.16 V
|   rising waveform, R_fixture 50, V_fixture 0.80867V: 20-80 % time 208ps typ, 252ps min, 172ps max; typ from 0.16 V to 0.809 V
[GND Clamp]
| Voltage   I(typ)   I(min)   I(max)
-808.7mV  -80.37mA   -222mA     -80.74mA
-783.7mV  -71.17mA   -133.6mA   -74.56mA
-758.7mV  -64.24mA   -91.22mA   -67.91mA
-733.7mV  -57.98mA   -69.4mA    -60.91mA
-708.7mV  -51.92mA   -56.75mA   -53.79mA
-658.7mV  -40.22mA   -41.7mA    -39.91mA
-583.7mV  -24.39mA   -26.41mA   -21.78mA
-508.7mV  -11.91mA   -14.51mA   -8.63mA
-458.7mV  -6.021mA   -8.437mA   -3.317mA
-408.7mV  -2.346mA   -4.117mA   -840.2uA
-308.7mV  -146.6uA   -492.3uA   -18.47uA
791.3mV   1.208nA    35.61nA    -1.245pA
[POWER Clamp]
| Voltage   I(typ)   I(min)   I(max)
-808.7mV  33.02nA    676.5nA    257.7pA
-583.7mV  30.32nA    637.8nA    188.8pA
-533.7mV  26.33nA    621.6nA    64.6pA
-508.7mV  20.08nA    604.6nA    40.81pA
-483.7mV  11.74nA    565.4nA    32.71pA
-458.7mV  5.847nA    479.8nA    29.41pA
-408.7mV  2.125nA    211.3nA    26.04pA
-383.7mV  1.712nA    122.8nA    24.67pA
-358.7mV  1.545nA    77.92nA    23.35pA
-333.7mV  1.471nA    57.06nA    22.03pA
-258.7mV  1.389nA    40.71nA    18.08pA
-8.67mV   1.225nA    35.32nA    4.944pA
[Pulldown]
| Voltage   I(typ)   I(min)   I(max)
-808.7mV  -126.9mA   -259.7mA   -140.3mA
-783.7mV  -117.8mA   -171.3mA   -134.3mA
-758.7mV  -110.7mA   -128.8mA   -127.7mA
-733.7mV  -104.2mA   -106.7mA   -120.4mA
-683.7mV  -91.18mA   -84.64mA   -105.2mA
-633.7mV  -78.39mA   -71.22mA   -90.23mA
-508.7mV  -50.6mA    -45.42mA   -59.21mA
-408.7mV  -35.42mA   -30.55mA   -44.02mA
141.3mV   11.67mA    9.059mA    15.86mA
441.3mV   27.35mA    21.54mA    36.19mA
791.3mV   34.41mA    27.45mA    44.37mA
1.616V    36.98mA    29.67mA    47.19mA
[Pullup]
| Voltage   I(typ)   I(min)   I(max)
-808.7mV  24.53mA    19.25mA    32.08mA
-183.7mV  13.04mA    10.2mA     17.5mA
391.3mV   -32.8mA    -26.53mA   -42.02mA
1.066V    -76.76mA   -65.87mA   -92.16mA
1.266V    -93.85mA   -88.49mA   -106.1mA
1.441V    -129.3mA   -125.9mA   -137.9mA
1.491V    -141.7mA   -145.7mA   -151.7mA
1.516V    -148mA     -164.6mA   -159mA
1.541V    -154.4mA   -200.1mA   -166.5mA
1.566V    -161mA     -272.7mA   -174.1mA
1.591V    -168.1mA   -428.9mA   -181.6mA
1.616V    -177.3mA   -772.1mA   -188.9mA
[Falling Waveform]
R_fixture = 50
V_fixture = 0.0000V
V_fixture_min = 0.0000V
V_fixture_max = 0.0000V
|   Time   V(typ)   V(min)   V(max)
0s        660.3mV    592.9mV    733.1mV
380ps     661.4mV    593.3mV    731.9mV
520ps     638.5mV    587.6mV    675mV
600ps     600.6mV    567.4mV    584.1mV
680ps     534.2mV    535.1mV    422.9mV
830ps     307.8mV    421.8mV    119.8mV
1ns       72.85mV    213mV      9.63mV
1.17ns    7.933mV    51.8mV     2.528mV
1.37ns    2.424mV    5.338mV    1.604mV
5ns       20.76uV    38.97uV    11.94uV
[Rising Waveform]
R_fixture = 50
V_fixture = 0.0000V
V_fixture_min = 0.0000V
V_fixture_max = 0.0000V
|   Time   V(typ)   V(min)   V(max)
0s        6.06uV     7.22uV     4.921uV
840ps     -3.194mV   -2.876mV   11.79mV
940ps     4.316mV    -2.413mV   87.34mV
1.06ns    57.85mV    4.33mV     246.4mV
1.34ns    325.4mV    135.1mV    592.8mV
1.54ns    496.7mV    287.2mV    672.7mV
1.78ns    586.9mV    437.9mV    703.5mV
2.2ns     633.1mV    537.9mV    722.2mV
3.05ns    654.7mV    580.6mV    731.3mV
10ns      660.3mV    592.9mV    733.1mV
[Falling Waveform]
R_fixture = 50
V_fixture = 0.80867V
V_fixture_min = 0.76428V
V_fixture_max = 0.85294V
|   Time   V(typ)   V(min)   V(max)
0s        808.7mV    764.3mV    852.9mV
800ps     802.4mV    760.9mV    829.2mV
1.02ns    747.6mV    749.7mV    624.4mV
1.2ns     610.1mV    694.5mV    375.9mV
1.32ns    496.1mV    629.4mV    264.6mV
1.56ns    312.8mV    471.2mV    183mV
1.8ns     236.9mV    344.9mV    155.2mV
2.3ns     185.5mV    243.2mV    135.8mV
3.2ns     165mV      200.5mV    128.8mV
10ns      160mV      187.5mV    127.5mV
[Rising Waveform]
R_fixture = 50
V_fixture = 0.80867V
V_fixture_min = 0.76428V
V_fixture_max = 0.85294V
|   Time   V(typ)   V(min)   V(max)
0s        160mV      187.5mV    127.5mV
410ps     159.7mV    187.5mV    127.4mV
560ps     181mV      194.3mV    175.4mV
660ps     229.7mV    221.7mV    296.2mV
770ps     357.8mV    278.2mV    614.3mV
830ps     486.1mV    329.2mV    721.1mV
940ps     687.8mV    485.5mV    805.9mV
1.11ns    781.3mV    693.7mV    844.9mV
1.6ns     809.4mV    764.1mV    853.5mV
7ns       808.7mV    764.3mV    852.9mV
[Ramp]
| variable   typ   min   max
dV/dt_r   0.39616V/448.66p   0.35575V/557.64p   0.43988V/342.78p
dV/dt_f   0.38923V/492.51p   0.34604V/647.58p   0.43528V/354.91p
R_load = 50
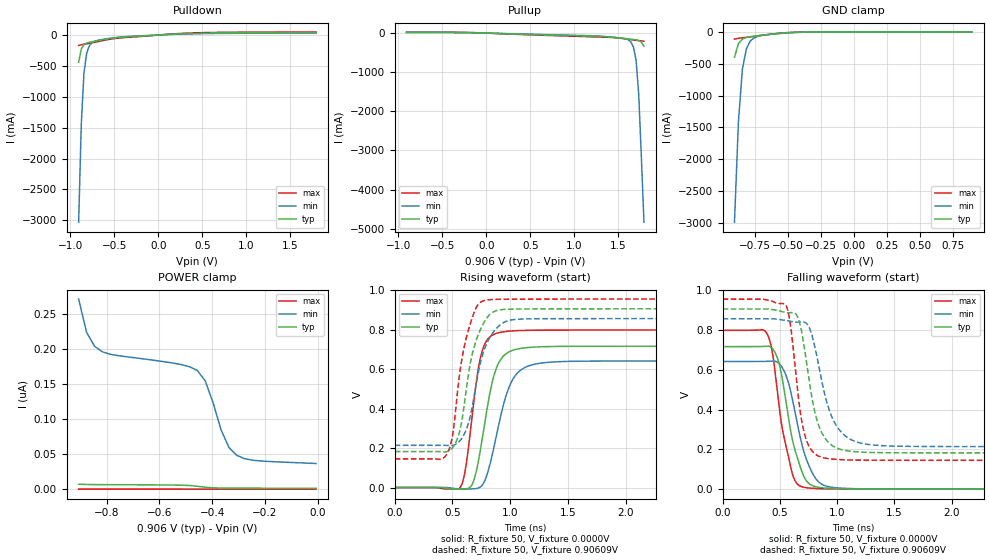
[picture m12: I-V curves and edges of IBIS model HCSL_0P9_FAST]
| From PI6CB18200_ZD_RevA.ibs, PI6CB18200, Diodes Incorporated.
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[Model]   HCSL_0P9_FAST
Model_type Output
Vref=0.9000V
Vmeas=900mV
| variable   typ   min   max
C_comp   2.200pF   2.170pF   2.230pF
[Voltage Range]   0.90609V   0.85650V   0.95550V
[POWER Clamp Reference]   0.90609V   0.85650V   0.95550V
[GND Clamp Reference]   0.0000V   0.0000V   0.0000V
[Pullup Reference]   0.90609V   0.85650V   0.95550V
[Pulldown Reference]   0.0000V   0.0000V   0.0000V
[Temperature Range]   25   85   -40
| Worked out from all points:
|   slope of the pulldown table from 0 to 0.136 V, typ, clamps not added: 12.1 ohm
|   slope of the pullup table from 0 to 0.136 V, typ, clamps not added: 13.2 ohm
|   GND clamp passes 1 mA (typ) near -0.37 V on its own axis
|   falling waveform, R_fixture 50, V_fixture 0.0000V: 20-80 % time 145ps typ, 162ps min, 129ps max; typ from 0.717 V to 0 V
|   rising waveform, R_fixture 50, V_fixture 0.0000V: 20-80 % time 135ps typ, 164ps min, 106ps max; typ from 0 V to 0.717 V
|   falling waveform, R_fixture 50, V_fixture 0.90609V: 20-80 % time 136ps typ, 170ps min, 103ps max; typ from 0.906 V to 0.182 V
|   rising waveform, R_fixture 50, V_fixture 0.90609V: 20-80 % time 137ps typ, 149ps min, 124ps max; typ from 0.182 V to 0.906 V
[GND Clamp]
| Voltage   I(typ)   I(min)   I(max)
-906.1mV  -394.8mA   -2.992A    -111.1mA
-876.1mV  -181.4mA   -1.409A    -98.21mA
-846.1mV  -110.3mA   -583mA     -89.83mA
-816.1mV  -84.16mA   -264.3mA   -82.58mA
-786.1mV  -71.98mA   -139.6mA   -75.25mA
-756.1mV  -63.63mA   -88.35mA   -67.26mA
-666.1mV  -41.95mA   -43.55mA   -41.94mA
-516.1mV  -12.97mA   -15.56mA   -9.674mA
-396.1mV  -1.762mA   -3.322mA   -556.7uA
893.9mV   1.274nA    37.22nA    5.408pA
[POWER Clamp]
| Voltage   I(typ)   I(min)   I(max)
-906.1mV  7.102nA    272nA      64.05pA
-876.1mV  6.695nA    224.4nA    62.63pA
-846.1mV  6.537nA    204.6nA    61.28pA
-816.1mV  6.464nA    196.5nA    59.93pA
-516.1mV  5.725nA    178.2nA    42.48pA
-456.1mV  4.154nA    169.7nA    33.31pA
-426.1mV  2.718nA    154.9nA    31.21pA
-366.1mV  1.642nA    84.73nA    27.91pA
-336.1mV  1.538nA    59.52nA    26.32pA
-306.1mV  1.492nA    48.22nA    24.74pA
-246.1mV  1.442nA    41.44nA    21.59pA
-6.09mV   1.286nA    36.73nA    8.971pA
[Pulldown]
| Voltage   I(typ)   I(min)   I(max)
-906.1mV  -441mA     -3.03A     -170.1mA
-876.1mV  -227.7mA   -1.447A    -157.3mA
-846.1mV  -156.6mA   -620.6mA   -149mA
-816.1mV  -130.6mA   -302mA     -142mA
-786.1mV  -118.6mA   -177.3mA   -135mA
-756.1mV  -110.1mA   -125.9mA   -127mA
-666.1mV  -86.67mA   -79.52mA   -99.89mA
-426.1mV  -37.54mA   -32.71mA   -46.06mA
293.9mV   20.99mA    16.43mA    28.11mA
713.9mV   33.61mA    26.75mA    43.5mA
1.794V    37.21mA    29.87mA    47.47mA
[Pullup]
| Voltage   I(typ)   I(min)   I(max)
-906.1mV  18.82mA    14.78mA    24.99mA
-156.1mV  9.295mA    7.313mA    12.41mA
1.224V    -81.1mA    -71.37mA   -96.53mA
1.554V    -133.6mA   -133mA     -141.2mA
1.614V    -148.7mA   -170.9mA   -158.1mA
1.644V    -156.3mA   -224.4mA   -167.1mA
1.674V    -164.3mA   -354.5mA   -176.2mA
1.704V    -173.8mA   -686.8mA   -185.2mA
1.734V    -189.7mA   -1.549A    -193.6mA
1.764V    -227.7mA   -3.147A    -201.3mA
1.794V    -336.2mA   -4.832A    -208.5mA
[Falling Waveform]
R_fixture = 50
V_fixture = 0.0000V
V_fixture_min = 0.0000V
V_fixture_max = 0.0000V
|   Time   V(typ)   V(min)   V(max)
0s        716.5mV    641.8mV    798.5mV
390ps     719.3mV    642.9mV    779.3mV
440ps     703.4mV    644.5mV    667.8mV
490ps     637.9mV    632.9mV    432.3mV
590ps     306.2mV    501.7mV    122mV
640ps     180.9mV    365.4mV    35.1mV
700ps     76.68mV    207.5mV    10.64mV
820ps     10.96mV    47.71mV    3.131mV
1ns       2.473mV    6.597mV    765.8uV
5ns       13.71uV    17uV       10.75uV
[Rising Waveform]
R_fixture = 50
V_fixture = 0.0000V
V_fixture_min = 0.0000V
V_fixture_max = 0.0000V
|   Time   V(typ)   V(min)   V(max)
0s        6.448uV    7.731uV    5.429uV
570ps     -8.199mV   -7.428mV   2.892mV
610ps     -7.333mV   -7.839mV   85.54mV
670ps     15.48mV    -7.246mV   360.7mV
750ps     219.5mV    6.821mV    676.6mV
830ps     496.4mV    130.6mV    766.8mV
900ps     631.8mV    317mV      785mV
1.03ns    697.2mV    556mV      794.5mV
1.27ns    713.7mV    631.1mV    797.9mV
5ns       716.5mV    641.8mV    798.5mV
[Falling Waveform]
R_fixture = 50
V_fixture = 0.90609V
V_fixture_min = 0.85650V
V_fixture_max = 0.95550V
|   Time   V(typ)   V(min)   V(max)
0s        906.1mV    856.5mV    955.5mV
550ps     887.6mV    848.7mV    926.8mV
590ps     887.5mV    844.5mV    835.1mV
650ps     872.6mV    839.7mV    521.3mV
710ps     724.7mV    839.9mV    289mV
790ps     428.2mV    752.9mV    186.3mV
870ps     279.3mV    532.5mV    159.4mV
1.02ns    201.8mV    297.7mV    148.5mV
1.28ns    184.8mV    224.2mV    145.5mV
5ns       182.3mV    213.9mV    145.1mV
[Rising Waveform]
R_fixture = 50
V_fixture = 0.90609V
V_fixture_min = 0.85650V
V_fixture_max = 0.95550V
|   Time   V(typ)   V(min)   V(max)
0s        182.3mV    213.9mV    145mV
450ps     181.4mV    213.5mV    168mV
500ps     201.3mV    213mV      260.8mV
550ps     259.7mV    228.6mV    520.4mV
620ps     499.5mV    294.8mV    759.7mV
680ps     696.4mV    438.7mV    876.6mV
780ps     843.8mV    706.6mV    948.7mV
910ps     900.6mV    823.3mV    954.3mV
1.08ns    905.1mV    853.7mV    955mV
5ns       906.1mV    856.5mV    955.5mV
[Ramp]
| variable   typ   min   max
dV/dt_r   0.42991V/134.54p   0.38507V/164.18p   0.47912V/106.41p
dV/dt_f   0.43427V/135.65p   0.38554V/170.24p   0.48626V/103.30p
R_load = 50
